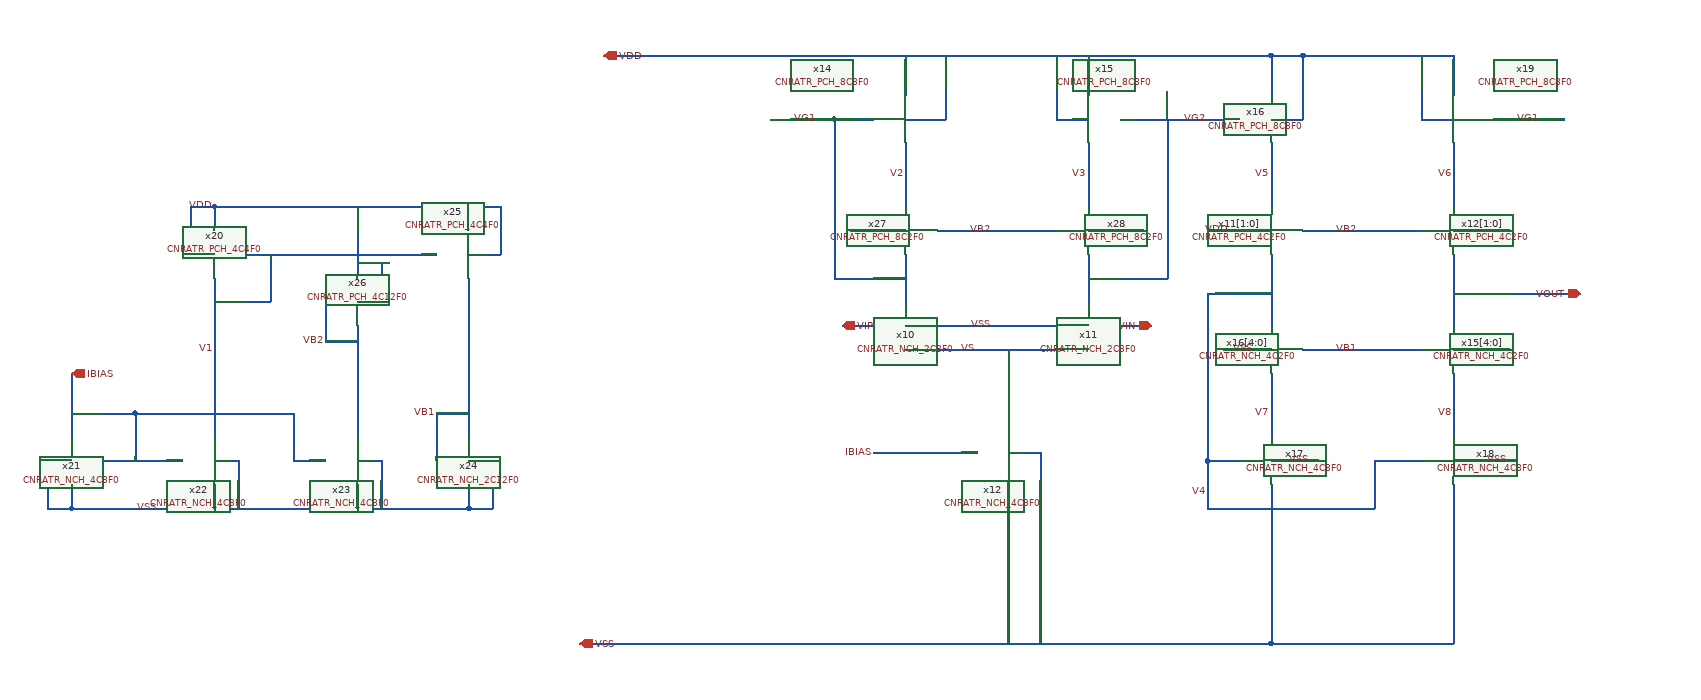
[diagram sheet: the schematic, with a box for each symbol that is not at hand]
v {xschem version=3.4.4 file_version=1.2
}
G {}
K {}
V {}
S {}
E {}
N 2120 90 2350 90 {
lab=VSS}
N 2120 120 2350 120 {
lab=VS}
N 2250 120 2250 170 {
lab=VS}
N 2250 170 2250 220 {
lab=VS}
N 2040 90 2080 90 {
lab=VIP}
N 2390 90 2430 90 {
lab=VIN}
N 1740 -250 2580 -250 {
lab=VDD}
N 2580 -250 2580 -200 {
lab=VDD}
N 2350 -250 2350 -200 {
lab=VDD}
N 2390 -170 2540 -170 {
lab=VG2}
N 2120 -250 2120 -200 {
lab=VDD}
N 1710 490 1820 490 {
lab=VSS}
N 1820 490 2580 490 {
lab=VSS}
N 2580 490 2650 490 {
lab=VSS}
N 2450 -170 2450 -110 {
lab=VG2}
N 2080 250 2210 250 {
lab=IBIAS}
N 2250 250 2290 250 {
lab=VSS}
N 2290 250 2290 330 {
lab=VSS}
N 2120 -170 2170 -170 {
lab=VDD}
N 2170 -250 2170 -170 {
lab=VDD}
N 2310 -170 2350 -170 {
lab=VDD}
N 2310 -250 2310 -170 {
lab=VDD}
N 2580 -170 2620 -170 {
lab=VDD}
N 2620 -250 2620 -170 {
lab=VDD}
N 2580 -250 2620 -250 {
lab=VDD}
N 2160 -30 2310 -30 {
lab=VB2}
N 2350 0 2350 60 {
lab=VG2}
N 2120 0 2120 60 {
lab=VG1}
N 2120 -140 2120 -60 {
lab=V2}
N 2350 -140 2350 -60 {
lab=V3}
N 2030 -170 2080 -170 {
lab=VG1}
N 2030 -170 2030 30 {
lab=VG1}
N 2030 30 2120 30 {
lab=VG1}
N 2350 30 2450 30 {
lab=VG2}
N 2450 -110 2450 30 {
lab=VG2}
N 2350 -30 2420 -30 {
lab=VDD}
N 2050 -30 2120 -30 {
lab=VDD}
N 1950 -170 2030 -170 {
lab=VG1}
N 2620 -30 2770 -30 {
lab=VB2}
N 2580 -140 2580 -60 {
lab=V5}
N 2500 -30 2580 -30 {
lab=VDD}
N 2810 -30 2880 -30 {
lab=VDD}
N 2810 -140 2810 -60 {
lab=V6}
N 2850 -170 2950 -170 {
lab=VG1}
N 2620 -250 2810 -250 {
lab=VDD}
N 2810 -250 2810 -200 {
lab=VDD}
N 2770 -170 2810 -170 {
lab=VDD}
N 2770 -250 2770 -170 {
lab=VDD}
N 2620 120 2770 120 {
lab=VB1}
N 2810 0 2810 90 {
lab=VOUT}
N 2580 0 2580 90 {
lab=V4}
N 2810 150 2810 230 {
lab=V8}
N 2580 150 2580 230 {
lab=V7}
N 2500 260 2540 260 {
lab=V4}
N 2500 50 2500 260 {
lab=V4}
N 2500 50 2580 50 {
lab=V4}
N 2520 120 2580 120 {
lab=VSS}
N 2580 290 2580 440 {
lab=VSS}
N 2580 440 2580 490 {
lab=VSS}
N 2810 290 2810 490 {
lab=VSS}
N 2650 490 2810 490 {
lab=VSS}
N 2500 260 2500 320 {
lab=V4}
N 2500 320 2710 320 {
lab=V4}
N 2710 260 2710 320 {
lab=V4}
N 2710 260 2770 260 {
lab=V4}
N 2580 260 2640 260 {
lab=VSS}
N 2810 260 2890 260 {
lab=VSS}
N 2810 50 2970 50 {
lab=VOUT}
N 2810 120 2880 120 {
lab=VSS}
N 1070 290 1070 320 {
lab=VSS}
N 1070 320 1570 320 {
lab=VSS}
N 1570 290 1570 320 {
lab=VSS}
N 1430 290 1430 320 {
lab=VSS}
N 1250 290 1250 320 {
lab=VSS}
N 1040 260 1070 260 {
lab=VSS}
N 1040 260 1040 320 {
lab=VSS}
N 1040 320 1070 320 {
lab=VSS}
N 1570 260 1600 260 {
lab=VSS}
N 1600 260 1600 320 {
lab=VSS}
N 1570 320 1600 320 {
lab=VSS}
N 1430 260 1460 260 {
lab=VSS}
N 1460 260 1460 320 {
lab=VSS}
N 1250 260 1280 260 {
lab=VSS}
N 1280 260 1280 320 {
lab=VSS}
N 1110 260 1210 260 {
lab=IBIAS}
N 1070 150 1070 230 {
lab=IBIAS}
N 1070 200 1150 200 {
lab=IBIAS}
N 1150 200 1150 260 {
lab=IBIAS}
N 1150 200 1350 200 {
lab=IBIAS}
N 1350 200 1350 260 {
lab=IBIAS}
N 1350 260 1390 260 {
lab=IBIAS}
N 1250 30 1250 230 {
lab=V1}
N 1570 30 1570 230 {
lab=VB1}
N 1290 0 1530 0 {
lab=V1}
N 1250 -60 1250 -30 {
lab=VDD}
N 1250 -60 1570 -60 {
lab=VDD}
N 1570 -60 1570 -30 {
lab=VDD}
N 1220 0 1250 0 {
lab=VDD}
N 1220 -60 1220 0 {
lab=VDD}
N 1220 -60 1250 -60 {
lab=VDD}
N 1570 0 1610 0 {
lab=VDD}
N 1610 -60 1610 0 {
lab=VDD}
N 1570 -60 1610 -60 {
lab=VDD}
N 1320 0 1320 60 {
lab=V1}
N 1250 60 1320 60 {
lab=V1}
N 1430 90 1430 230 {
lab=VB2}
N 1430 -60 1430 30 {
lab=VDD}
N 1390 60 1390 110 {
lab=VB2}
N 1390 110 1430 110 {
lab=VB2}
N 1430 60 1460 60 {
lab=VDD}
N 1460 10 1460 60 {
lab=VDD}
N 1430 10 1460 10 {
lab=VDD}
N 1530 200 1530 260 {
lab=VB1}
N 1530 200 1570 200 {
lab=VB1}
N 2290 330 2290 490 {
lab=VSS}
N 2250 280 2250 490 {
lab=VSS}
C {devices/iopin.sym} 1740 -250 0 1 {name=p7 lab=VDD}
C {devices/iopin.sym} 2430 90 0 0 {name=p8 lab=VIN}
C {devices/iopin.sym} 2040 90 0 1 {name=p9 lab=VIP}
C {devices/iopin.sym} 1710 490 0 1 {name=p10 lab=VSS}
C {/home/ocheid/aicex/ip/cnr_atr_sky130nm/design/CNR_ATR_SKY130NM/CNRATR_NCH_2C8F0.sym} 2080 90 0 0 {name=x10}
C {/home/ocheid/aicex/ip/cnr_atr_sky130nm/design/CNR_ATR_SKY130NM/CNRATR_NCH_2C8F0.sym} 2390 90 0 1 {name=x11}
C {/home/ocheid/aicex/ip/cnr_atr_sky130nm/design/CNR_ATR_SKY130NM/CNRATR_NCH_4C8F0.sym} 2210 250 0 0 {name=x12 }
C {devices/iopin.sym} 1070 150 1 1 {name=p11 lab=IBIAS}
C {/home/ocheid/aicex/ip/cnr_atr_sky130nm/design/CNR_ATR_SKY130NM/CNRATR_PCH_8C8F0.sym} 2080 -170 0 0 {name=x14}
C {/home/ocheid/aicex/ip/cnr_atr_sky130nm/design/CNR_ATR_SKY130NM/CNRATR_PCH_8C8F0.sym} 2390 -170 0 1 {name=x15}
C {/home/ocheid/aicex/ip/cnr_atr_sky130nm/design/CNR_ATR_SKY130NM/CNRATR_PCH_8C8F0.sym} 2540 -170 0 0 {name=x16}
C {/home/ocheid/aicex/ip/cnr_atr_sky130nm/design/CNR_ATR_SKY130NM/CNRATR_NCH_4C8F0.sym} 2540 260 0 0 {name=x17}
C {/home/ocheid/aicex/ip/cnr_atr_sky130nm/design/CNR_ATR_SKY130NM/CNRATR_NCH_4C8F0.sym} 2770 260 0 0 {name=x18}
C {devices/lab_wire.sym} 2230 90 0 0 {name=l2 sig_type=std_logic lab=VSS}
C {devices/lab_wire.sym} 2210 120 0 0 {name=l4 sig_type=std_logic lab=VS}
C {devices/lab_pin.sym} 2230 -30 3 1 {name=l5 sig_type=std_logic lab=VB2}
C {devices/lab_pin.sym} 2080 250 2 1 {name=l7 sig_type=std_logic lab=IBIAS}
C {devices/iopin.sym} 2970 50 0 0 {name=p12 lab=VOUT}
C {/home/ocheid/aicex/ip/cnr_atr_sky130nm/design/CNR_ATR_SKY130NM/CNRATR_PCH_4C2F0.sym} 2620 -30 0 1 {name=x11[1:0]}
C {devices/lab_pin.sym} 2690 -30 3 1 {name=l8 sig_type=std_logic lab=VB2}
C {/home/ocheid/aicex/ip/cnr_atr_sky130nm/design/CNR_ATR_SKY130NM/CNRATR_PCH_8C8F0.sym} 2850 -170 0 1 {name=x19}
C {/home/ocheid/aicex/ip/cnr_atr_sky130nm/design/CNR_ATR_SKY130NM/CNRATR_NCH_4C2F0.sym} 2620 120 0 1 {name=x16[4:0]}
C {devices/lab_pin.sym} 2690 120 3 1 {name=l9 sig_type=std_logic lab=VB1}
C {devices/lab_wire.sym} 2630 260 0 0 {name=l10 sig_type=std_logic lab=VSS}
C {devices/lab_wire.sym} 2880 260 0 0 {name=l11 sig_type=std_logic lab=VSS}
C {devices/lab_wire.sym} 2530 -30 0 0 {name=l12 sig_type=std_logic lab=VDD}
C {devices/lab_wire.sym} 2870 -30 0 0 {name=l13 sig_type=std_logic lab=VDD}
C {devices/lab_wire.sym} 2410 -30 0 0 {name=l14 sig_type=std_logic lab=VDD}
C {devices/lab_wire.sym} 2080 -30 0 0 {name=l16 sig_type=std_logic lab=VDD}
C {devices/lab_wire.sym} 2560 120 0 0 {name=l17 sig_type=std_logic lab=VSS}
C {devices/lab_wire.sym} 2870 120 0 0 {name=l18 sig_type=std_logic lab=VSS}
C {devices/lab_wire.sym} 2010 -170 0 0 {name=l19 sig_type=std_logic lab=VG1}
C {devices/lab_wire.sym} 2920 -170 0 0 {name=l20 sig_type=std_logic lab=VG1}
C {devices/lab_wire.sym} 2500 -170 0 0 {name=l21 sig_type=std_logic lab=VG2}
C {/home/ocheid/aicex/ip/cnr_atr_sky130nm/design/CNR_ATR_SKY130NM/CNRATR_PCH_4C4F0.sym} 1290 0 0 1 {name=x20}
C {/home/ocheid/aicex/ip/cnr_atr_sky130nm/design/CNR_ATR_SKY130NM/CNRATR_NCH_4C8F0.sym} 1110 260 0 1 {name=x21 }
C {/home/ocheid/aicex/ip/cnr_atr_sky130nm/design/CNR_ATR_SKY130NM/CNRATR_NCH_4C8F0.sym} 1210 260 0 0 {name=x22 }
C {/home/ocheid/aicex/ip/cnr_atr_sky130nm/design/CNR_ATR_SKY130NM/CNRATR_NCH_4C8F0.sym} 1390 260 0 0 {name=x23 }
C {/home/ocheid/aicex/ip/cnr_atr_sky130nm/design/CNR_ATR_SKY130NM/CNRATR_NCH_2C12F0.sym} 1530 260 0 0 {name=x24 }
C {/home/ocheid/aicex/ip/cnr_atr_sky130nm/design/CNR_ATR_SKY130NM/CNRATR_PCH_4C4F0.sym} 1530 0 0 0 {name=x25}
C {/home/ocheid/aicex/ip/cnr_atr_sky130nm/design/CNR_ATR_SKY130NM/CNRATR_PCH_4C12F0.sym} 1390 60 0 0 {name=x26}
C {devices/lab_wire.sym} 1250 -60 0 0 {name=l22 sig_type=std_logic lab=VDD}
C {devices/lab_wire.sym} 1180 320 0 0 {name=l23 sig_type=std_logic lab=VSS}
C {devices/lab_pin.sym} 1390 110 2 1 {name=l25 sig_type=std_logic lab=VB2}
C {devices/lab_pin.sym} 1530 200 2 1 {name=l26 sig_type=std_logic lab=VB1}
C {devices/lab_pin.sym} 1250 120 2 1 {name=l27 sig_type=std_logic lab=V1}
C {devices/lab_pin.sym} 2120 -100 2 1 {name=l28 sig_type=std_logic lab=V2}
C {devices/lab_pin.sym} 2350 -100 2 1 {name=l29 sig_type=std_logic lab=V3}
C {devices/lab_pin.sym} 2500 300 2 1 {name=l30 sig_type=std_logic lab=V4}
C {devices/lab_pin.sym} 2580 -100 2 1 {name=l31 sig_type=std_logic lab=V5}
C {devices/lab_pin.sym} 2810 -100 2 1 {name=l32 sig_type=std_logic lab=V6}
C {devices/lab_pin.sym} 2580 200 2 1 {name=l33 sig_type=std_logic lab=V7}
C {devices/lab_pin.sym} 2810 200 2 1 {name=l34 sig_type=std_logic lab=V8}
C {/home/ocheid/aicex/ip/cnr_atr_sky130nm/design/CNR_ATR_SKY130NM/CNRATR_NCH_4C2F0.sym} 2770 120 0 0 {name=x15[4:0]}
C {/home/ocheid/aicex/ip/cnr_atr_sky130nm/design/CNR_ATR_SKY130NM/CNRATR_PCH_8C2F0.sym} 2160 -30 0 1 {name=x27}
C {/home/ocheid/aicex/ip/cnr_atr_sky130nm/design/CNR_ATR_SKY130NM/CNRATR_PCH_8C2F0.sym} 2310 -30 0 0 {name=x28}
C {/home/ocheid/aicex/ip/cnr_atr_sky130nm/design/CNR_ATR_SKY130NM/CNRATR_PCH_4C2F0.sym} 2770 -30 0 0 {name=x12[1:0]}
